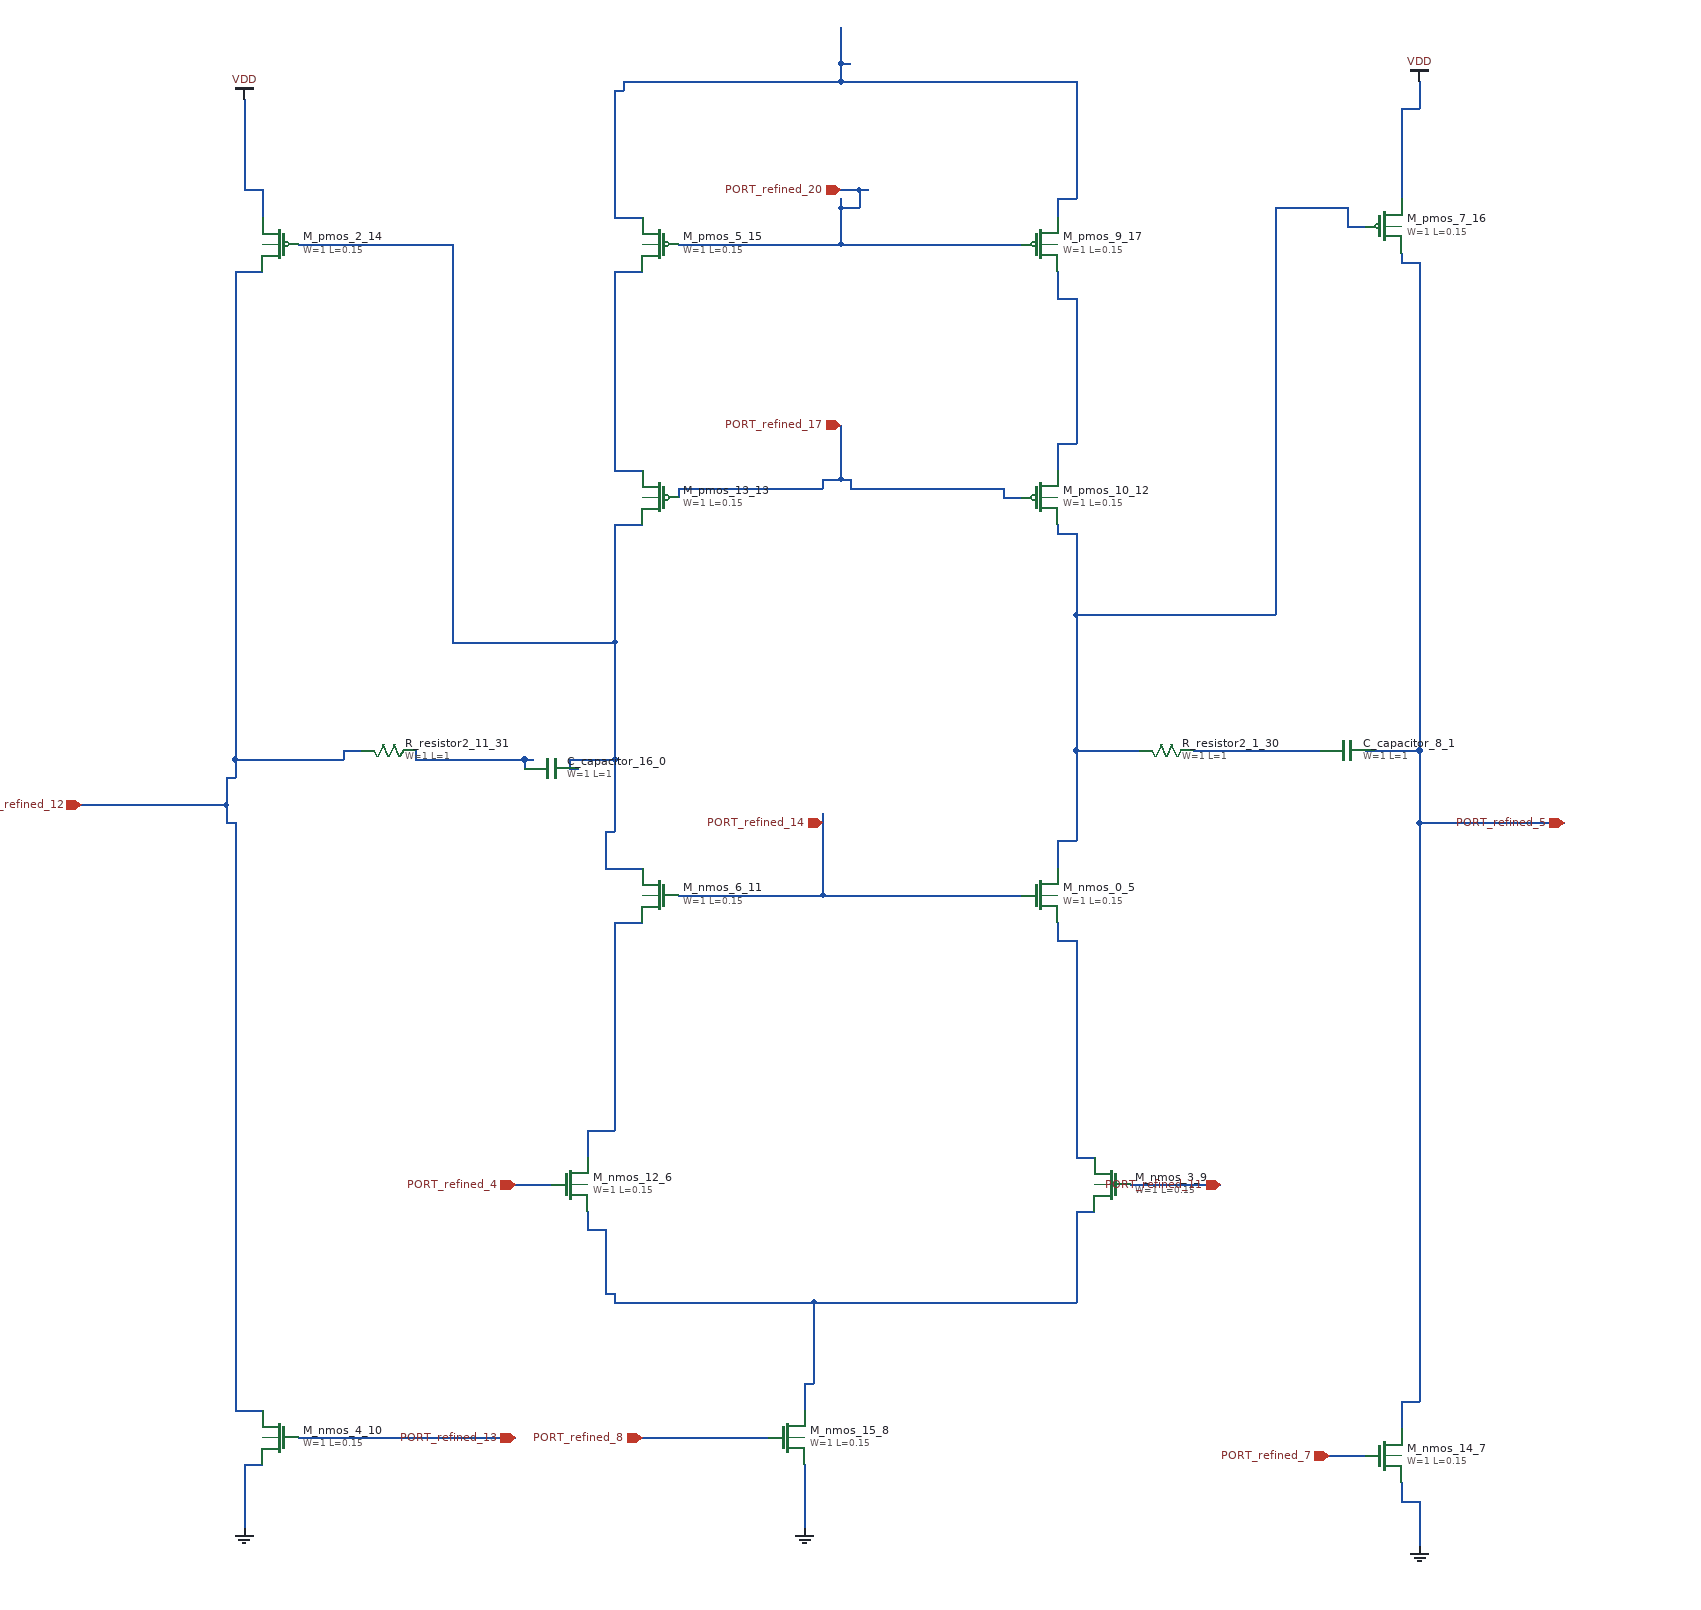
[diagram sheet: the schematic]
v {xschem version=3.4.8 file_version=1.2}
G {}
K {}
V {}
S {}
E {}
C {sky130_fd_pr/cap_mim_m3_1.sym} 680 820 3 0 {name="C_capacitor_16_0" model=cap_mim_m3_1 W=1 L=1 MF=1 spiceprefix=X}
C {sky130_fd_pr/cap_mim_m3_1.sym} 1560 800 1 0 {name="C_capacitor_8_1" model=cap_mim_m3_1 W=1 L=1 MF=1 spiceprefix=X}
C {devices/gnd.sym} 1640 1680 0 0 {name="l_gnd_23_2" lab="GND"}
C {devices/gnd.sym} 960 1660 0 0 {name="l_gnd_26_3" lab="GND"}
C {devices/gnd.sym} 340 1660 0 0 {name="l_gnd_30_4" lab="GND"}
C {sky130_fd_pr/nfet3_01v8.sym} 1220 960 0 0 {name="M_nmos_0_5"
W=1
L=0.15
body=GND
nf=1
mult=1
ad="expr('int((@nf + 1)/2) * @W / @nf * 0.29')"
pd="expr('2*int((@nf + 1)/2) * (@W / @nf + 0.29)')"
as="expr('int((@nf + 2)/2) * @W / @nf * 0.29')"
ps="expr('2*int((@nf + 2)/2) * (@W / @nf + 0.29)')"
nrd="expr('0.29 / @W ')" nrs="expr('0.29 / @W ')"
sa=0 sb=0 sd=0
model=nfet_01v8
spiceprefix=X
}
C {sky130_fd_pr/nfet3_01v8.sym} 700 1280 0 0 {name="M_nmos_12_6"
W=1
L=0.15
body=GND
nf=1
mult=1
ad="expr('int((@nf + 1)/2) * @W / @nf * 0.29')"
pd="expr('2*int((@nf + 1)/2) * (@W / @nf + 0.29)')"
as="expr('int((@nf + 2)/2) * @W / @nf * 0.29')"
ps="expr('2*int((@nf + 2)/2) * (@W / @nf + 0.29)')"
nrd="expr('0.29 / @W ')" nrs="expr('0.29 / @W ')"
sa=0 sb=0 sd=0
model=nfet_01v8
spiceprefix=X
}
C {sky130_fd_pr/nfet3_01v8.sym} 1600 1580 0 0 {name="M_nmos_14_7"
W=1
L=0.15
body=GND
nf=1
mult=1
ad="expr('int((@nf + 1)/2) * @W / @nf * 0.29')"
pd="expr('2*int((@nf + 1)/2) * (@W / @nf + 0.29)')"
as="expr('int((@nf + 2)/2) * @W / @nf * 0.29')"
ps="expr('2*int((@nf + 2)/2) * (@W / @nf + 0.29)')"
nrd="expr('0.29 / @W ')" nrs="expr('0.29 / @W ')"
sa=0 sb=0 sd=0
model=nfet_01v8
spiceprefix=X
}
C {sky130_fd_pr/nfet3_01v8.sym} 940 1560 0 0 {name="M_nmos_15_8"
W=1
L=0.15
body=GND
nf=1
mult=1
ad="expr('int((@nf + 1)/2) * @W / @nf * 0.29')"
pd="expr('2*int((@nf + 1)/2) * (@W / @nf + 0.29)')"
as="expr('int((@nf + 2)/2) * @W / @nf * 0.29')"
ps="expr('2*int((@nf + 2)/2) * (@W / @nf + 0.29)')"
nrd="expr('0.29 / @W ')" nrs="expr('0.29 / @W ')"
sa=0 sb=0 sd=0
model=nfet_01v8
spiceprefix=X
}
C {sky130_fd_pr/nfet3_01v8.sym} 1300 1280 0 1 {name="M_nmos_3_9"
W=1
L=0.15
body=GND
nf=1
mult=1
ad="expr('int((@nf + 1)/2) * @W / @nf * 0.29')"
pd="expr('2*int((@nf + 1)/2) * (@W / @nf + 0.29)')"
as="expr('int((@nf + 2)/2) * @W / @nf * 0.29')"
ps="expr('2*int((@nf + 2)/2) * (@W / @nf + 0.29)')"
nrd="expr('0.29 / @W ')" nrs="expr('0.29 / @W ')"
sa=0 sb=0 sd=0
model=nfet_01v8
spiceprefix=X
}
C {sky130_fd_pr/nfet3_01v8.sym} 380 1560 0 1 {name="M_nmos_4_10"
W=1
L=0.15
body=GND
nf=1
mult=1
ad="expr('int((@nf + 1)/2) * @W / @nf * 0.29')"
pd="expr('2*int((@nf + 1)/2) * (@W / @nf + 0.29)')"
as="expr('int((@nf + 2)/2) * @W / @nf * 0.29')"
ps="expr('2*int((@nf + 2)/2) * (@W / @nf + 0.29)')"
nrd="expr('0.29 / @W ')" nrs="expr('0.29 / @W ')"
sa=0 sb=0 sd=0
model=nfet_01v8
spiceprefix=X
}
C {sky130_fd_pr/nfet3_01v8.sym} 800 960 0 1 {name="M_nmos_6_11"
W=1
L=0.15
body=GND
nf=1
mult=1
ad="expr('int((@nf + 1)/2) * @W / @nf * 0.29')"
pd="expr('2*int((@nf + 1)/2) * (@W / @nf + 0.29)')"
as="expr('int((@nf + 2)/2) * @W / @nf * 0.29')"
ps="expr('2*int((@nf + 2)/2) * (@W / @nf + 0.29)')"
nrd="expr('0.29 / @W ')" nrs="expr('0.29 / @W ')"
sa=0 sb=0 sd=0
model=nfet_01v8
spiceprefix=X
}
C {sky130_fd_pr/pfet3_01v8.sym} 1220 520 0 0 {name="M_pmos_10_12"
W=1
L=0.15
body=VDD
nf=1
mult=1
ad="expr('int((@nf + 1)/2) * @W / @nf * 0.29')"
pd="expr('2*int((@nf + 1)/2) * (@W / @nf + 0.29)')"
as="expr('int((@nf + 2)/2) * @W / @nf * 0.29')"
ps="expr('2*int((@nf + 2)/2) * (@W / @nf + 0.29)')"
nrd="expr('0.29 / @W ')" nrs="expr('0.29 / @W ')"
sa=0 sb=0 sd=0
model=pfet_01v8
spiceprefix=X
}
C {sky130_fd_pr/pfet3_01v8.sym} 800 520 0 1 {name="M_pmos_13_13"
W=1
L=0.15
body=VDD
nf=1
mult=1
ad="expr('int((@nf + 1)/2) * @W / @nf * 0.29')"
pd="expr('2*int((@nf + 1)/2) * (@W / @nf + 0.29)')"
as="expr('int((@nf + 2)/2) * @W / @nf * 0.29')"
ps="expr('2*int((@nf + 2)/2) * (@W / @nf + 0.29)')"
nrd="expr('0.29 / @W ')" nrs="expr('0.29 / @W ')"
sa=0 sb=0 sd=0
model=pfet_01v8
spiceprefix=X
}
C {sky130_fd_pr/pfet3_01v8.sym} 380 240 0 1 {name="M_pmos_2_14"
W=1
L=0.15
body=VDD
nf=1
mult=1
ad="expr('int((@nf + 1)/2) * @W / @nf * 0.29')"
pd="expr('2*int((@nf + 1)/2) * (@W / @nf + 0.29)')"
as="expr('int((@nf + 2)/2) * @W / @nf * 0.29')"
ps="expr('2*int((@nf + 2)/2) * (@W / @nf + 0.29)')"
nrd="expr('0.29 / @W ')" nrs="expr('0.29 / @W ')"
sa=0 sb=0 sd=0
model=pfet_01v8
spiceprefix=X
}
C {sky130_fd_pr/pfet3_01v8.sym} 800 240 0 1 {name="M_pmos_5_15"
W=1
L=0.15
body=VDD
nf=1
mult=1
ad="expr('int((@nf + 1)/2) * @W / @nf * 0.29')"
pd="expr('2*int((@nf + 1)/2) * (@W / @nf + 0.29)')"
as="expr('int((@nf + 2)/2) * @W / @nf * 0.29')"
ps="expr('2*int((@nf + 2)/2) * (@W / @nf + 0.29)')"
nrd="expr('0.29 / @W ')" nrs="expr('0.29 / @W ')"
sa=0 sb=0 sd=0
model=pfet_01v8
spiceprefix=X
}
C {sky130_fd_pr/pfet3_01v8.sym} 1600 220 0 0 {name="M_pmos_7_16"
W=1
L=0.15
body=VDD
nf=1
mult=1
ad="expr('int((@nf + 1)/2) * @W / @nf * 0.29')"
pd="expr('2*int((@nf + 1)/2) * (@W / @nf + 0.29)')"
as="expr('int((@nf + 2)/2) * @W / @nf * 0.29')"
ps="expr('2*int((@nf + 2)/2) * (@W / @nf + 0.29)')"
nrd="expr('0.29 / @W ')" nrs="expr('0.29 / @W ')"
sa=0 sb=0 sd=0
model=pfet_01v8
spiceprefix=X
}
C {sky130_fd_pr/pfet3_01v8.sym} 1220 240 0 0 {name="M_pmos_9_17"
W=1
L=0.15
body=VDD
nf=1
mult=1
ad="expr('int((@nf + 1)/2) * @W / @nf * 0.29')"
pd="expr('2*int((@nf + 1)/2) * (@W / @nf + 0.29)')"
as="expr('int((@nf + 2)/2) * @W / @nf * 0.29')"
ps="expr('2*int((@nf + 2)/2) * (@W / @nf + 0.29)')"
nrd="expr('0.29 / @W ')" nrs="expr('0.29 / @W ')"
sa=0 sb=0 sd=0
model=pfet_01v8
spiceprefix=X
}
C {devices/vdd.sym} 1640 60 0 0 {name="l_port_17_18" lab="VDD"}
C {devices/vdd.sym} 340 80 0 0 {name="l_port_18_19" lab="VDD"}
C {devices/ipin.sym} 640 1280 0 0 {name="p_port_19_20" lab="PORT_refined_4"}
C {devices/ipin.sym} 1800 880 0 0 {name="p_port_20_21" lab="PORT_refined_5"}
C {devices/ipin.sym} 1420 1280 0 0 {name="p_port_21_22" lab="PORT_refined_11"}
C {devices/ipin.sym} 1540 1580 0 0 {name="p_port_22_23" lab="PORT_refined_7"}
C {devices/ipin.sym} 980 880 0 0 {name="p_port_24_24" lab="PORT_refined_14"}
C {devices/ipin.sym} 160 860 0 0 {name="p_port_25_25" lab="PORT_refined_12"}
C {devices/ipin.sym} 1000 180 0 0 {name="p_port_27_26" lab="PORT_refined_20"}
C {devices/ipin.sym} 640 1560 0 0 {name="p_port_28_27" lab="PORT_refined_13"}
C {devices/ipin.sym} 1000 440 0 0 {name="p_port_29_28" lab="PORT_refined_17"}
C {devices/ipin.sym} 780 1560 0 0 {name="p_port_31_29" lab="PORT_refined_8"}
C {sky130_fd_pr/res_generic_po.sym} 1360 800 1 0 {name="R_resistor2_1_30"
W=1
L=1
model=res_generic_po
spiceprefix=X
mult=1}
C {sky130_fd_pr/res_generic_po.sym} 500 800 1 0 {name="R_resistor2_11_31"
W=1
L=1
model=res_generic_po
spiceprefix=X
mult=1}
N 740 930 780 930 {}
N 740 890 750 890 {}
N 700 820 710 820 {}
N 700 810 750 810 {}
N 570 680 750 680 {}
N 750 550 780 550 {}
N 400 240 570 240 {}
N 570 680 570 240 {}
N 700 820 700 810 {}
N 740 930 740 890 {}
N 750 890 750 810 {}
N 750 810 750 680 {}
N 750 680 750 550 {}
N 530 810 650 810 {}
N 650 810 660 810 {}
N 530 810 530 800 {}
N 650 820 650 810 {}
N 1260 1250 1280 1250 {}
N 1240 1010 1260 1010 {}
N 1240 1010 1240 990 {}
N 1260 1250 1260 1010 {}
N 1320 1280 1420 1280 {}
N 330 1530 360 1530 {}
N 320 880 330 880 {}
N 160 860 320 860 {}
N 320 830 330 830 {}
N 330 810 450 810 {}
N 450 800 470 800 {}
N 330 270 360 270 {}
N 320 880 320 860 {}
N 320 860 320 830 {}
N 330 1530 330 880 {}
N 330 830 330 810 {}
N 330 810 330 270 {}
N 450 810 450 800 {}
N 400 1560 640 1560 {}
N 820 960 980 960 {}
N 980 960 1200 960 {}
N 980 960 980 880 {}
N 980 880 980 870 {}
N 1240 460 1260 460 {}
N 1240 300 1260 300 {}
N 1240 490 1240 460 {}
N 1240 300 1240 270 {}
N 1260 460 1260 300 {}
N 1240 900 1260 900 {}
N 1260 800 1330 800 {}
N 1260 650 1480 650 {}
N 1240 560 1260 560 {}
N 1560 220 1580 220 {}
N 1480 200 1560 200 {}
N 1240 930 1240 900 {}
N 1240 560 1240 550 {}
N 1260 900 1260 800 {}
N 1260 800 1260 650 {}
N 1260 650 1260 560 {}
N 1480 650 1480 200 {}
N 1560 220 1560 200 {}
N 1180 520 1200 520 {}
N 820 510 980 510 {}
N 1010 510 1180 510 {}
N 980 500 1000 500 {}
N 1000 500 1010 500 {}
N 820 520 820 510 {}
N 980 510 980 500 {}
N 1000 500 1000 440 {}
N 1010 510 1010 500 {}
N 1180 520 1180 510 {}
N 750 490 780 490 {}
N 750 270 780 270 {}
N 750 490 750 270 {}
N 750 210 780 210 {}
N 1240 190 1260 190 {}
N 750 70 760 70 {}
N 760 60 1000 60 {}
N 1000 60 1260 60 {}
N 1000 40 1010 40 {}
N 750 210 750 70 {}
N 760 70 760 60 {}
N 1000 60 1000 40 {}
N 1000 40 1000 0 {}
N 1240 210 1240 190 {}
N 1260 190 1260 60 {}
N 720 1220 750 1220 {}
N 750 990 780 990 {}
N 720 1250 720 1220 {}
N 750 1220 750 990 {}
N 820 240 1000 240 {}
N 1000 240 1200 240 {}
N 1000 200 1020 200 {}
N 1000 180 1020 180 {}
N 1020 180 1030 180 {}
N 1000 240 1000 200 {}
N 1000 200 1000 190 {}
N 1020 200 1020 180 {}
N 340 180 360 180 {}
N 1620 90 1640 90 {}
N 340 180 340 80 {}
N 360 210 360 180 {}
N 1620 190 1620 90 {}
N 1640 90 1640 60 {}
N 960 1500 970 1500 {}
N 750 1410 970 1410 {}
N 970 1410 1260 1410 {}
N 740 1400 750 1400 {}
N 720 1330 740 1330 {}
N 1260 1310 1280 1310 {}
N 720 1330 720 1310 {}
N 740 1400 740 1330 {}
N 750 1410 750 1400 {}
N 960 1530 960 1500 {}
N 970 1500 970 1410 {}
N 1260 1410 1260 1310 {}
N 640 1280 680 1280 {}
N 1620 1520 1640 1520 {}
N 1640 880 1800 880 {}
N 1580 800 1590 800 {}
N 1590 800 1640 800 {}
N 1620 260 1640 260 {}
N 1620 1550 1620 1520 {}
N 1620 260 1620 250 {}
N 1640 1520 1640 880 {}
N 1640 880 1640 800 {}
N 1640 800 1640 260 {}
N 1620 1630 1640 1630 {}
N 340 1590 360 1590 {}
N 340 1660 340 1590 {}
N 960 1660 960 1590 {}
N 1620 1630 1620 1610 {}
N 1640 1680 1640 1630 {}
N 1540 1580 1580 1580 {}
N 780 1560 920 1560 {}
N 1390 800 1530 800 {}
